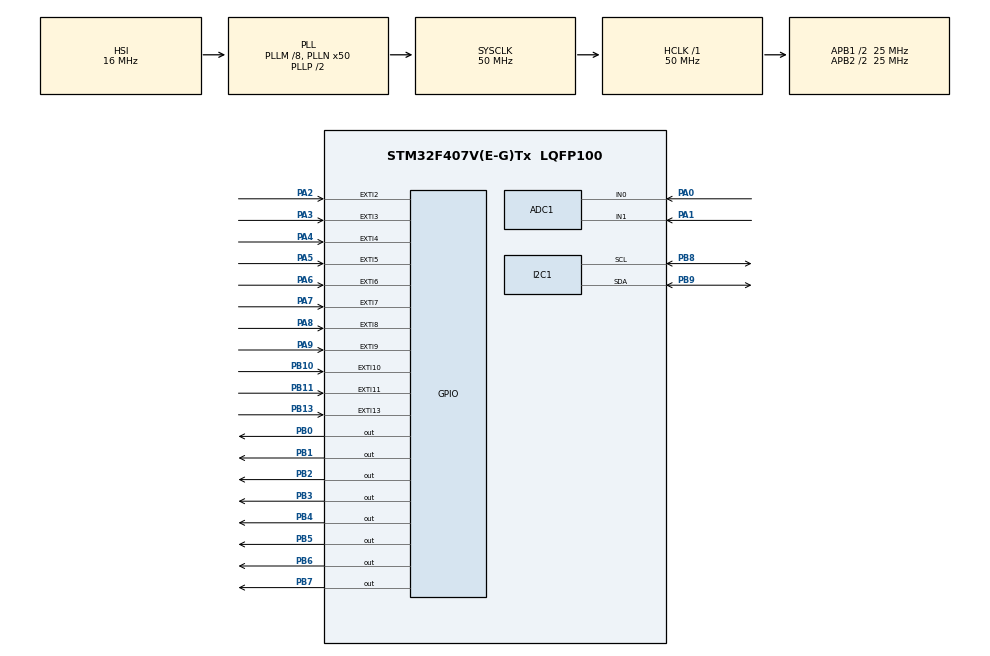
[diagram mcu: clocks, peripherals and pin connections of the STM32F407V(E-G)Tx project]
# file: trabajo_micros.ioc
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ADC1.Channel-0\#ChannelRegularConversion=ADC_CHANNEL_0
ADC1.NbrOfConversionFlag=1
ADC1.Rank-0\#ChannelRegularConversion=1
ADC1.SamplingTime-0\#ChannelRegularConversion=ADC_SAMPLETIME_3CYCLES
ADC1.master=1
Mcu.Family=STM32F4
Mcu.Name=STM32F407V(E-G)Tx
Mcu.Package=LQFP100
NVIC.EXTI15_10_IRQn=true\:0\:0\:false\:false\:true\:true\:true\:true
NVIC.PriorityGroup=NVIC_PRIORITYGROUP_0
NVIC.TIM1_UP_TIM10_IRQn=true\:0\:0\:false\:false\:true\:false\:true\:true
NVIC.TimeBase=TIM1_UP_TIM10_IRQn
NVIC.TimeBaseIP=TIM1
PA0-WKUP.Signal=ADCx_IN0
PA1.Signal=ADCx_IN1
PA2.Signal=GPXTI2
PA3.Signal=GPXTI3
PA4.Signal=GPXTI4
PA5.Signal=GPXTI5
PA6.Signal=GPXTI6
PA7.Signal=GPXTI7
PA8.Signal=GPXTI8
PA9.Signal=GPXTI9
PB0.Signal=GPIO_Output
PB1.Signal=GPIO_Output
PB10.Signal=GPXTI10
PB11.Signal=GPXTI11
PB13.Signal=GPXTI13
PB2.Signal=GPIO_Output
PB3.Signal=GPIO_Output
PB4.Signal=GPIO_Output
PB5.Signal=GPIO_Output
PB6.Signal=GPIO_Output
PB7.Signal=GPIO_Output
PB8.Mode=I2C
PB8.Signal=I2C1_SCL
PB9.Mode=I2C
PB9.Signal=I2C1_SDA
PH0-OSC_IN.Mode=HSE-External-Oscillator
PH0-OSC_IN.Signal=RCC_OSC_IN
PH1-OSC_OUT.Mode=HSE-External-Oscillator
PH1-OSC_OUT.Signal=RCC_OSC_OUT
ProjectManager.HeapSize=0x200
ProjectManager.StackSize=0x400
ProjectManager.TargetToolchain=STM32CubeIDE
RCC.48MHZClocksFreq_Value=14285714.285714285
RCC.AHBFreq_Value=50000000
RCC.APB1CLKDivider=RCC_HCLK_DIV2
RCC.APB1Freq_Value=25000000
RCC.APB1TimFreq_Value=50000000
RCC.APB2CLKDivider=RCC_HCLK_DIV2
RCC.APB2Freq_Value=25000000
RCC.APB2TimFreq_Value=50000000
RCC.CortexFreq_Value=50000000
RCC.HCLKFreq_Value=50000000
RCC.HSE_VALUE=8000000
RCC.HSI_VALUE=16000000
RCC.LSE_VALUE=32768
RCC.PLLM=8
RCC.PLLN=50
RCC.PLLQ=7
RCC.SYSCLKFreq_VALUE=50000000
RCC.SYSCLKSource=RCC_SYSCLKSOURCE_PLLCLK
RCC.VCOOutputFreq_Value=100000000
SH.ADCx_IN0.0=ADC1_IN0,IN0
SH.ADCx_IN1.0=ADC1_IN1,IN1
TIM6.Period=0xffff-1
TIM6.Prescaler=50-1
VP_SYS_VS_tim1.Mode=TIM1
VP_TIM6_VS_ClockSourceINT.Mode=Enable_Timer
board=STM32F407G-DISC1

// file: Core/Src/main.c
/* USER CODE BEGIN Header */
/**
  ******************************************************************************
  * @file           : main.c
  * @brief          : Main program body
  ******************************************************************************
  * @attention
  *
  * <h2><center>&copy; Copyright (c) 2022 STMicroelectronics.
  * All rights reserved.</center></h2>
  *
  * This software component is licensed by ST under BSD 3-Clause license,
  * the "License"; You may not use this file except in compliance with the
  * License. You may obtain a copy of the License at:
  *                        opensource.org/licenses/BSD-3-Clause
  *
  ******************************************************************************
  */
/* USER CODE END Header */
#include "main.h"

/* USER CODE BEGIN Includes */
#include "Luces.h"
#include "Toldo.h"
#include "Humidificador.h"

/* USER CODE END Includes */

ADC_HandleTypeDef hadc1;

I2C_HandleTypeDef hi2c1;

TIM_HandleTypeDef htim6;

void SystemClock_Config(void);
static void MX_GPIO_Init(void);
static void MX_ADC1_Init(void);
static void MX_I2C1_Init(void);
static void MX_TIM6_Init(void);

/* USER CODE BEGIN 0 */

//Interrupciones botones:
volatile int button_int = 0;
int boton_presionado = 0;
//Antirrebotes botones:
int debouncer(volatile int *button_int, GPIO_TypeDef *GPIO_port,
		uint16_t GPIO_number) {
	static uint8_t button_count = 0;
	static int counter = 0;

	if (*button_int == 1) {
		if (button_count == 0) {
			counter = HAL_GetTick();
			button_count++;
		}
		if (HAL_GetTick() - counter >= 20) {
			counter = HAL_GetTick();
			if (HAL_GPIO_ReadPin(GPIO_port, GPIO_number) != 1) {
				button_count = 1;
			} else {
				button_count++;
			}
			if (button_count == 4) { //Periodo antirebotes
				button_count = 0;
				*button_int = 0;
				return 1;
			}
		}
	}
	return 0;
}
//todos los pulsadores y finales de carrera
void HAL_GPIO_EXTI_Callback(uint16_t GPIO_Pin) {
	HAL_GPIO_WritePin(GPIOD, GPIO_PIN_12, 1);
	HAL_GPIO_WritePin(GPIOD, GPIO_PIN_13, 1);
	if (GPIO_Pin == GPIO_PIN_2) { 			//2 3 4 corresponden a las luces
		button_int = 1;
		boton_presionado = 2;//OFF
	} else if (GPIO_Pin == GPIO_PIN_3) {
		button_int = 1;
		boton_presionado = 3;//ON
	} else if (GPIO_Pin == GPIO_PIN_4) {
		button_int = 1;
		boton_presionado = 4;//AUTO
	} else if (GPIO_Pin == GPIO_PIN_5) { 	//5 6 7 8 9 corresponden al toldo
		button_int = 1;
		boton_presionado = 5;//OFF
	} else if (GPIO_Pin == GPIO_PIN_6) {
		button_int = 1;
		boton_presionado = 6;//SUBIENDO
	} else if (GPIO_Pin == GPIO_PIN_7) {
		button_int = 1;
		boton_presionado = 7;//BAJANDO
	} else if (GPIO_Pin == GPIO_PIN_8) {
		button_int = 1;
		boton_presionado = 8;//FIN DE CARRERA ARRIBA
	} else if (GPIO_Pin == GPIO_PIN_9) {
		button_int = 1;
		boton_presionado = 9;//FIN DE CARRERA ABAJO
	} else if (GPIO_Pin == GPIO_PIN_10) { 	//10 11 12 corresponden al humidificador
		button_int = 1;
		boton_presionado = 10;//OFF
	} else if (GPIO_Pin == GPIO_PIN_11) {
		button_int = 1;
		boton_presionado = 11;//ON
	} else if (GPIO_Pin == GPIO_PIN_13) {
		button_int = 1;
		boton_presionado = 13;//AUTO
	}
}

/* USER CODE END 0 */

int main(void)
{

  /* MCU Configuration--------------------------------------------------------*/

  /* Reset of all peripherals, Initializes the Flash interface and the Systick. */
  HAL_Init();

  /* Configure the system clock */
  SystemClock_Config();

  /* Initialize all configured peripherals */
  MX_GPIO_Init();
  MX_ADC1_Init();
  MX_I2C1_Init();
  MX_TIM6_Init();
  /* USER CODE BEGIN 2 */

  setLuces(0);
  cambiarEstadoToldo(0);
  setEstadoHumidificador(0);
  HAL_TIM_Base_Start(&htim6);

  /* USER CODE END 2 */

  /* Infinite loop */
  /* USER CODE BEGIN WHILE */
  while (1)
  {
	  switch (boton_presionado) {
	  	  		case 2:		//luces off
	  	  			if (debouncer(&button_int, GPIOA, GPIO_PIN_2)) {
	  	  				setLuces(0);
	  	  			}
	  	  			break;
	  	  		case 3:		//luces on
	  	  			if (debouncer(&button_int, GPIOA, GPIO_PIN_3)) {
	  	  				setLuces(1);
	  	  			}
	  	  			break;
	  	  		case 4:		//luces auto
	  	  			if (debouncer(&button_int, GPIOA, GPIO_PIN_4)) {
	  	  				setLuces(2);
	  	  			}
	  	  			break;
	  	  		case 5:		//toldo stop
	  	  			if (debouncer(&button_int, GPIOA, GPIO_PIN_5))  {
	  	  				cambiarEstadoToldo(0);
	  	  			}
	  	  			break;
	  	  		case 6:		//toldo subir
	  	  			if (debouncer(&button_int, GPIOA, GPIO_PIN_6)) {
	  	  				cambiarEstadoToldo(1);
	  	  			}
	  	  			break;
	  	  		case 7:		//toldo bajar
	  	  			if (debouncer(&button_int, GPIOA, GPIO_PIN_7)) {
	  	  				cambiarEstadoToldo(2);
	  	  			}
	  	  			break;
	  	  		case 8:		//toldo fin carrera arriba
	  	  			if (debouncer(&button_int, GPIOA, GPIO_PIN_8)) {
	  	  			  	cambiarEstadoToldo(3);
	  	  			}
	  	  			break;
	  	  		case 9:		//toldo fin carrera abajo
	  	  			if (debouncer(&button_int, GPIOA, GPIO_PIN_9)) {
	  	  			  	cambiarEstadoToldo(4);
	  	  			}
	  	  			break;
	  	  		case 10:		//humidificador off
	  	  			if (debouncer(&button_int, GPIOB, GPIO_PIN_10)) {
	  	  				setEstadoHumidificador(0);
	  	  			}
	  	  			break;
	  	  		case 11:		//humidificador on
	  	  			if (debouncer(&button_int, GPIOB, GPIO_PIN_11)) {
	  	  				setEstadoHumidificador(1);
	  	  			}
	  	  			break;
	  	  		case 13:		//humidificador auto
	  	  			if (debouncer(&button_int, GPIOB, GPIO_PIN_13)) {
	  	  				setEstadoHumidificador(2);
	  	  			}
	  	  			break;
	  	  }
	  	  luces();
	  	  Humidificador();

    /* USER CODE END WHILE */

  }
}

void SystemClock_Config(void)
{
  RCC_OscInitTypeDef RCC_OscInitStruct = {0};
  RCC_ClkInitTypeDef RCC_ClkInitStruct = {0};

  /** Configure the main internal regulator output voltage
  */
  __HAL_RCC_PWR_CLK_ENABLE();
  __HAL_PWR_VOLTAGESCALING_CONFIG(PWR_REGULATOR_VOLTAGE_SCALE1);
  /** Initializes the RCC Oscillators according to the specified parameters
  * in the RCC_OscInitTypeDef structure.
  */
  RCC_OscInitStruct.OscillatorType = RCC_OSCILLATORTYPE_HSI;
  RCC_OscInitStruct.HSIState = RCC_HSI_ON;
  RCC_OscInitStruct.HSICalibrationValue = RCC_HSICALIBRATION_DEFAULT;
  RCC_OscInitStruct.PLL.PLLState = RCC_PLL_ON;
  RCC_OscInitStruct.PLL.PLLSource = RCC_PLLSOURCE_HSI;
  RCC_OscInitStruct.PLL.PLLM = 8;
  RCC_OscInitStruct.PLL.PLLN = 50;
  RCC_OscInitStruct.PLL.PLLP = RCC_PLLP_DIV2;
  RCC_OscInitStruct.PLL.PLLQ = 7;
  if (HAL_RCC_OscConfig(&RCC_OscInitStruct) != HAL_OK)
  {
    Error_Handler();
  }
  /** Initializes the CPU, AHB and APB buses clocks
  */
  RCC_ClkInitStruct.ClockType = RCC_CLOCKTYPE_HCLK|RCC_CLOCKTYPE_SYSCLK
                              |RCC_CLOCKTYPE_PCLK1|RCC_CLOCKTYPE_PCLK2;
  RCC_ClkInitStruct.SYSCLKSource = RCC_SYSCLKSOURCE_PLLCLK;
  RCC_ClkInitStruct.AHBCLKDivider = RCC_SYSCLK_DIV1;
  RCC_ClkInitStruct.APB1CLKDivider = RCC_HCLK_DIV2;
  RCC_ClkInitStruct.APB2CLKDivider = RCC_HCLK_DIV2;

  if (HAL_RCC_ClockConfig(&RCC_ClkInitStruct, FLASH_LATENCY_1) != HAL_OK)
  {
    Error_Handler();
  }
}

static void MX_ADC1_Init(void)
{

  ADC_ChannelConfTypeDef sConfig = {0};

  /** Configure the global features of the ADC (Clock, Resolution, Data Alignment and number of conversion)
  */
  hadc1.Instance = ADC1;
  hadc1.Init.ClockPrescaler = ADC_CLOCK_SYNC_PCLK_DIV2;
  hadc1.Init.Resolution = ADC_RESOLUTION_12B;
  hadc1.Init.ScanConvMode = DISABLE;
  hadc1.Init.ContinuousConvMode = DISABLE;
  hadc1.Init.DiscontinuousConvMode = DISABLE;
  hadc1.Init.ExternalTrigConvEdge = ADC_EXTERNALTRIGCONVEDGE_NONE;
  hadc1.Init.ExternalTrigConv = ADC_SOFTWARE_START;
  hadc1.Init.DataAlign = ADC_DATAALIGN_RIGHT;
  hadc1.Init.NbrOfConversion = 1;
  hadc1.Init.DMAContinuousRequests = DISABLE;
  hadc1.Init.EOCSelection = ADC_EOC_SINGLE_CONV;
  if (HAL_ADC_Init(&hadc1) != HAL_OK)
  {
    Error_Handler();
  }
  /** Configure for the selected ADC regular channel its corresponding rank in the sequencer and its sample time.
  */
  sConfig.Channel = ADC_CHANNEL_0;
  sConfig.Rank = 1;
  sConfig.SamplingTime = ADC_SAMPLETIME_3CYCLES;
  if (HAL_ADC_ConfigChannel(&hadc1, &sConfig) != HAL_OK)
  {
    Error_Handler();
  }

}

static void MX_I2C1_Init(void)
{

  hi2c1.Instance = I2C1;
  hi2c1.Init.ClockSpeed = 100000;
  hi2c1.Init.DutyCycle = I2C_DUTYCYCLE_2;
  hi2c1.Init.OwnAddress1 = 0;
  hi2c1.Init.AddressingMode = I2C_ADDRESSINGMODE_7BIT;
  hi2c1.Init.DualAddressMode = I2C_DUALADDRESS_DISABLE;
  hi2c1.Init.OwnAddress2 = 0;
  hi2c1.Init.GeneralCallMode = I2C_GENERALCALL_DISABLE;
  hi2c1.Init.NoStretchMode = I2C_NOSTRETCH_DISABLE;
  if (HAL_I2C_Init(&hi2c1) != HAL_OK)
  {
    Error_Handler();
  }

}

static void MX_TIM6_Init(void)
{

  TIM_MasterConfigTypeDef sMasterConfig = {0};

  htim6.Instance = TIM6;
  htim6.Init.Prescaler = 50-1;
  htim6.Init.CounterMode = TIM_COUNTERMODE_UP;
  htim6.Init.Period = 0xffff-1;
  htim6.Init.AutoReloadPreload = TIM_AUTORELOAD_PRELOAD_DISABLE;
  if (HAL_TIM_Base_Init(&htim6) != HAL_OK)
  {
    Error_Handler();
  }
  sMasterConfig.MasterOutputTrigger = TIM_TRGO_RESET;
  sMasterConfig.MasterSlaveMode = TIM_MASTERSLAVEMODE_DISABLE;
  if (HAL_TIMEx_MasterConfigSynchronization(&htim6, &sMasterConfig) != HAL_OK)
  {
    Error_Handler();
  }

}

static void MX_GPIO_Init(void)
{
  GPIO_InitTypeDef GPIO_InitStruct = {0};

  /* GPIO Ports Clock Enable */
  __HAL_RCC_GPIOH_CLK_ENABLE();
  __HAL_RCC_GPIOA_CLK_ENABLE();
  __HAL_RCC_GPIOB_CLK_ENABLE();
  __HAL_RCC_GPIOD_CLK_ENABLE();

  /*Configure GPIO pin Output Level */
  HAL_GPIO_WritePin(GPIOB, GPIO_PIN_0|GPIO_PIN_1|GPIO_PIN_2|GPIO_PIN_3
                          |GPIO_PIN_4|GPIO_PIN_5|GPIO_PIN_6|GPIO_PIN_7, GPIO_PIN_RESET);

  /*Configure GPIO pin Output Level */
  HAL_GPIO_WritePin(GPIOD, GPIO_PIN_12|GPIO_PIN_13|GPIO_PIN_14|GPIO_PIN_15, GPIO_PIN_RESET);

  /*Configure GPIO pins : PA2 PA3 PA4 PA5
                           PA6 PA7 PA8 PA9 */
  GPIO_InitStruct.Pin = GPIO_PIN_2|GPIO_PIN_3|GPIO_PIN_4|GPIO_PIN_5
                          |GPIO_PIN_6|GPIO_PIN_7|GPIO_PIN_8|GPIO_PIN_9;
  GPIO_InitStruct.Mode = GPIO_MODE_IT_RISING;
  GPIO_InitStruct.Pull = GPIO_NOPULL;
  HAL_GPIO_Init(GPIOA, &GPIO_InitStruct);

  /*Configure GPIO pins : PB0 PB1 PB2 PB3
                           PB4 PB5 PB6 PB7 */
  GPIO_InitStruct.Pin = GPIO_PIN_0|GPIO_PIN_1|GPIO_PIN_2|GPIO_PIN_3
                          |GPIO_PIN_4|GPIO_PIN_5|GPIO_PIN_6|GPIO_PIN_7;
  GPIO_InitStruct.Mode = GPIO_MODE_OUTPUT_PP;
  GPIO_InitStruct.Pull = GPIO_NOPULL;
  GPIO_InitStruct.Speed = GPIO_SPEED_FREQ_LOW;
  HAL_GPIO_Init(GPIOB, &GPIO_InitStruct);

  /*Configure GPIO pins : PB10 PB11 PB13 */
  GPIO_InitStruct.Pin = GPIO_PIN_10|GPIO_PIN_11|GPIO_PIN_13;
  GPIO_InitStruct.Mode = GPIO_MODE_IT_RISING;
  GPIO_InitStruct.Pull = GPIO_NOPULL;
  HAL_GPIO_Init(GPIOB, &GPIO_InitStruct);

  /*Configure GPIO pins : PD12 PD13 PD14 PD15 */
  GPIO_InitStruct.Pin = GPIO_PIN_12|GPIO_PIN_13|GPIO_PIN_14|GPIO_PIN_15;
  GPIO_InitStruct.Mode = GPIO_MODE_OUTPUT_PP;
  GPIO_InitStruct.Pull = GPIO_NOPULL;
  GPIO_InitStruct.Speed = GPIO_SPEED_FREQ_LOW;
  HAL_GPIO_Init(GPIOD, &GPIO_InitStruct);

  /* EXTI interrupt init*/
  HAL_NVIC_SetPriority(EXTI15_10_IRQn, 0, 0);
  HAL_NVIC_EnableIRQ(EXTI15_10_IRQn);

}

void HAL_TIM_PeriodElapsedCallback(TIM_HandleTypeDef *htim)
{
  if (htim->Instance == TIM1) {
    HAL_IncTick();
  }
}

void Error_Handler(void)
{
  __disable_irq();
  while (1)
  {
  }
}

/************************ (C) COPYRIGHT STMicroelectronics *****END OF FILE****/
